VERSION 5.8 ;
BUSBITCHARS "[]" ;
DIVIDERCHAR "/" ;
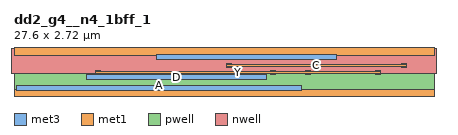
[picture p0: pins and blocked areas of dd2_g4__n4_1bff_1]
MACRO dd2_g4__n4_1bff_1
  CLASS CORE ;
  ORIGIN 0 0 ;
  SIZE 27.600 BY 2.720 ;
  SYMMETRY X Y ;
  SITE unithd ;
  PIN A
    DIRECTION INPUT ;
    USE SIGNAL ;
    ANTENNAGATEAREA 0.426000 ;
    PORT
      LAYER met3 ;
        RECT 0.185 0.175 18.915 0.505 ;
    END
  END A
  PIN B
    DIRECTION INPUT ;
    USE SIGNAL ;
    ANTENNAGATEAREA 0.213000 ;
    PORT
      LAYER met3 ;
        RECT 9.385 2.215 21.215 2.545 ;
    END
  END B
  PIN C
    DIRECTION INPUT ;
    USE SIGNAL ;
    ANTENNAGATEAREA 0.213000 ;
    PORT
      LAYER met1 ;
        RECT 13.990 1.670 14.310 1.730 ;
        RECT 25.490 1.670 25.810 1.730 ;
        RECT 13.985 1.730 25.815 1.870 ;
        RECT 13.990 1.870 14.310 1.930 ;
        RECT 25.490 1.870 25.810 1.930 ;
    END
  END C
  PIN D
    DIRECTION INPUT ;
    USE SIGNAL ;
    ANTENNAGATEAREA 0.213000 ;
    PORT
      LAYER met3 ;
        RECT 4.785 0.855 16.615 1.185 ;
    END
  END D
  PIN VGND
    DIRECTION INOUT ;
    USE GROUND ;
    SHAPE ABUTMENT ;
    PORT
      LAYER met1 ;
        RECT 0.000 -0.240 27.600 0.240 ;
    END
  END VGND
  PIN VNB
    DIRECTION INOUT ;
    USE GROUND ;
    PORT
      LAYER pwell ;
        RECT 0.000 0.000 27.600 1.305 ;
    END
  END VNB
  PIN VPB
    DIRECTION INOUT ;
    USE POWER ;
    PORT
      LAYER nwell ;
        RECT -0.190 1.305 27.790 2.910 ;
    END
  END VPB
  PIN VPWR
    DIRECTION INOUT ;
    USE POWER ;
    SHAPE ABUTMENT ;
    PORT
      LAYER met1 ;
        RECT 0.000 2.480 27.600 2.960 ;
    END
  END VPWR
  PIN Y
    DIRECTION OUTPUT ;
    USE SIGNAL ;
    ANTENNADIFFAREA 1.162800 ;
    PORT
      LAYER met1 ;
        RECT 5.365 1.230 5.685 1.290 ;
        RECT 16.865 1.230 17.185 1.290 ;
        RECT 19.165 1.230 19.485 1.290 ;
        RECT 23.765 1.230 24.085 1.290 ;
        RECT 5.360 1.290 24.090 1.430 ;
        RECT 5.365 1.430 5.685 1.490 ;
        RECT 16.865 1.430 17.185 1.490 ;
        RECT 19.165 1.430 19.485 1.490 ;
        RECT 23.765 1.430 24.085 1.490 ;
    END
  END Y
  OBS
    LAYER li1 ;
      RECT 0.000 -0.085 27.600 0.085 ;
      RECT 1.490 0.085 1.660 0.255 ;
      RECT 12.990 0.085 13.160 0.255 ;
      RECT 15.290 0.085 15.460 0.255 ;
      RECT 1.410 0.255 1.740 0.635 ;
      RECT 12.910 0.255 13.240 0.635 ;
      RECT 15.210 0.255 15.540 0.635 ;
      RECT 0.910 0.255 1.240 0.380 ;
      RECT 0.760 0.380 1.240 0.710 ;
      RECT 5.510 0.255 5.840 0.380 ;
      RECT 5.360 0.380 5.840 0.710 ;
      RECT 6.010 0.255 6.340 0.380 ;
      RECT 6.010 0.380 6.380 0.710 ;
      RECT 7.810 0.255 8.140 0.380 ;
      RECT 7.660 0.380 8.140 0.710 ;
      RECT 8.310 0.255 8.640 0.380 ;
      RECT 8.310 0.380 8.680 0.710 ;
      RECT 10.110 0.255 10.440 0.380 ;
      RECT 9.960 0.380 10.440 0.710 ;
      RECT 10.610 0.255 10.940 0.380 ;
      RECT 10.610 0.380 10.980 0.710 ;
      RECT 12.410 0.255 12.740 0.380 ;
      RECT 12.260 0.380 12.740 0.710 ;
      RECT 14.710 0.255 15.040 0.380 ;
      RECT 14.560 0.380 15.040 0.710 ;
      RECT 0.165 0.380 0.515 0.710 ;
      RECT 0.165 0.710 0.335 1.075 ;
      RECT 0.165 1.075 1.340 1.315 ;
      RECT 2.465 0.380 2.815 0.710 ;
      RECT 2.465 0.710 2.635 1.075 ;
      RECT 2.465 1.075 3.640 1.315 ;
      RECT 4.765 0.380 5.115 0.710 ;
      RECT 4.765 0.710 4.935 1.075 ;
      RECT 4.765 1.075 5.940 1.315 ;
      RECT 7.065 0.380 7.415 0.710 ;
      RECT 7.065 0.710 7.235 1.075 ;
      RECT 7.065 1.075 8.240 1.315 ;
      RECT 9.365 0.380 9.715 0.710 ;
      RECT 9.365 0.710 9.535 1.075 ;
      RECT 9.365 1.075 10.540 1.315 ;
      RECT 11.665 0.380 12.015 0.710 ;
      RECT 11.665 0.710 11.835 1.075 ;
      RECT 11.665 1.075 12.840 1.315 ;
      RECT 13.965 0.380 14.315 0.710 ;
      RECT 13.965 0.710 14.135 1.075 ;
      RECT 13.965 1.075 15.140 1.315 ;
      RECT 16.265 0.380 16.615 0.710 ;
      RECT 16.265 0.710 16.435 1.075 ;
      RECT 16.265 1.075 17.440 1.315 ;
      RECT 18.565 0.380 18.915 0.710 ;
      RECT 18.565 0.710 18.735 1.075 ;
      RECT 18.565 1.075 19.740 1.315 ;
      RECT 20.865 0.380 21.215 0.710 ;
      RECT 20.865 0.710 21.035 1.075 ;
      RECT 20.865 1.075 22.040 1.315 ;
      RECT 23.165 0.380 23.515 0.710 ;
      RECT 23.165 0.710 23.335 1.075 ;
      RECT 23.165 1.075 24.340 1.315 ;
      RECT 25.465 0.380 25.815 0.710 ;
      RECT 25.465 0.710 25.635 1.075 ;
      RECT 25.465 1.075 26.640 1.315 ;
      RECT 3.210 1.505 3.540 2.010 ;
      RECT 3.060 2.010 3.540 2.340 ;
      RECT 3.210 2.340 3.540 2.465 ;
      RECT 17.010 1.505 17.340 2.010 ;
      RECT 16.860 2.010 17.340 2.340 ;
      RECT 17.010 2.340 17.340 2.465 ;
      RECT 19.310 1.505 19.640 2.010 ;
      RECT 19.160 2.010 19.640 2.340 ;
      RECT 19.310 2.340 19.640 2.465 ;
      RECT 19.810 1.505 20.140 2.010 ;
      RECT 19.810 2.010 20.180 2.340 ;
      RECT 19.810 2.340 20.140 2.465 ;
      RECT 21.610 1.505 21.940 2.010 ;
      RECT 21.460 2.010 21.940 2.340 ;
      RECT 21.610 2.340 21.940 2.465 ;
      RECT 23.910 1.505 24.240 2.010 ;
      RECT 23.760 2.010 24.240 2.340 ;
      RECT 23.910 2.340 24.240 2.465 ;
      RECT 24.410 1.505 24.740 2.010 ;
      RECT 24.410 2.010 24.780 2.340 ;
      RECT 24.410 2.340 24.740 2.465 ;
      RECT 26.210 1.505 26.540 2.010 ;
      RECT 26.060 2.010 26.540 2.340 ;
      RECT 26.210 2.340 26.540 2.465 ;
      RECT 3.710 1.505 4.040 2.465 ;
      RECT 17.510 1.505 17.840 2.465 ;
      RECT 22.110 1.505 22.440 2.465 ;
      RECT 26.710 1.505 27.040 2.465 ;
      RECT 3.790 2.465 3.960 2.635 ;
      RECT 17.590 2.465 17.760 2.635 ;
      RECT 22.190 2.465 22.360 2.635 ;
      RECT 26.790 2.465 26.960 2.635 ;
      RECT 0.000 2.635 27.600 2.805 ;
    LAYER met1 ;
      RECT 0.185 0.380 0.515 0.710 ;
      RECT 2.485 0.380 2.815 0.710 ;
      RECT 4.785 0.380 5.115 0.710 ;
      RECT 5.360 0.380 5.690 0.710 ;
      RECT 6.050 0.380 6.380 0.710 ;
      RECT 7.085 0.380 7.415 0.710 ;
      RECT 7.660 0.380 7.990 0.710 ;
      RECT 8.350 0.380 8.680 0.710 ;
      RECT 9.385 0.380 9.715 0.710 ;
      RECT 9.960 0.380 10.290 0.710 ;
      RECT 10.650 0.380 10.980 0.710 ;
      RECT 12.260 0.380 12.590 0.710 ;
      RECT 13.985 0.380 14.315 0.710 ;
      RECT 14.560 0.380 14.890 0.710 ;
      RECT 16.285 0.380 16.615 0.710 ;
      RECT 18.585 0.380 18.915 0.710 ;
      RECT 20.885 0.380 21.215 0.710 ;
      RECT 25.485 0.380 25.815 0.710 ;
      RECT 0.760 0.380 1.090 0.710 ;
      RECT 11.685 0.380 12.015 0.710 ;
      RECT 23.185 0.380 23.515 0.710 ;
      RECT 0.765 0.710 1.085 0.850 ;
      RECT 3.065 0.790 3.385 0.850 ;
      RECT 11.690 0.710 12.010 0.850 ;
      RECT 23.190 0.710 23.510 0.850 ;
      RECT 0.760 0.850 23.515 0.990 ;
      RECT 0.765 0.990 1.085 1.050 ;
      RECT 3.065 0.990 3.385 1.050 ;
      RECT 11.690 0.990 12.010 1.050 ;
      RECT 23.190 0.990 23.510 1.050 ;
      RECT 24.455 0.790 24.775 0.850 ;
      RECT 26.065 0.790 26.385 0.850 ;
      RECT 24.450 0.850 26.390 0.990 ;
      RECT 24.455 0.990 24.775 1.050 ;
      RECT 26.065 0.990 26.385 1.050 ;
      RECT 6.055 1.670 6.375 1.730 ;
      RECT 7.665 1.670 7.985 1.730 ;
      RECT 9.965 1.670 10.285 1.730 ;
      RECT 6.050 1.730 10.290 1.870 ;
      RECT 6.055 1.870 6.375 1.930 ;
      RECT 7.665 1.870 7.985 1.930 ;
      RECT 9.965 1.870 10.285 1.930 ;
      RECT 3.060 2.010 3.390 2.340 ;
      RECT 16.860 2.010 17.190 2.340 ;
      RECT 19.160 2.010 19.490 2.340 ;
      RECT 19.850 2.010 20.180 2.340 ;
      RECT 21.460 2.010 21.790 2.340 ;
      RECT 23.760 2.010 24.090 2.340 ;
      RECT 24.450 2.010 24.780 2.340 ;
      RECT 26.060 2.010 26.390 2.340 ;
    LAYER met2 ;
      RECT 0.210 0.155 0.490 0.210 ;
      RECT 0.190 0.210 0.510 0.675 ;
      RECT 2.510 0.155 2.790 0.210 ;
      RECT 2.490 0.210 2.810 0.675 ;
      RECT 7.110 0.155 7.390 0.210 ;
      RECT 7.090 0.210 7.410 0.675 ;
      RECT 18.610 0.155 18.890 0.210 ;
      RECT 18.590 0.210 18.910 0.675 ;
      RECT 0.765 0.415 1.085 1.050 ;
      RECT 11.690 0.415 12.010 1.050 ;
      RECT 23.190 0.415 23.510 1.050 ;
      RECT 4.790 0.415 5.110 1.150 ;
      RECT 4.810 1.150 5.090 1.205 ;
      RECT 16.290 0.415 16.610 1.150 ;
      RECT 16.310 1.150 16.590 1.205 ;
      RECT 5.365 0.415 5.685 1.490 ;
      RECT 8.355 0.415 8.675 1.830 ;
      RECT 8.375 1.830 8.655 1.885 ;
      RECT 10.655 0.415 10.975 1.830 ;
      RECT 10.675 1.830 10.955 1.885 ;
      RECT 12.265 0.415 12.585 1.830 ;
      RECT 12.285 1.830 12.565 1.885 ;
      RECT 14.565 0.415 14.885 1.830 ;
      RECT 14.585 1.830 14.865 1.885 ;
      RECT 6.055 0.415 6.375 1.930 ;
      RECT 7.665 0.415 7.985 1.930 ;
      RECT 9.965 0.415 10.285 1.930 ;
      RECT 13.990 0.415 14.310 1.930 ;
      RECT 25.490 0.415 25.810 1.930 ;
      RECT 3.065 0.790 3.385 2.305 ;
      RECT 16.865 1.230 17.185 2.305 ;
      RECT 19.165 1.230 19.485 2.305 ;
      RECT 19.875 0.155 20.155 0.210 ;
      RECT 19.855 0.210 20.175 2.305 ;
      RECT 21.485 0.155 21.765 0.210 ;
      RECT 21.465 0.210 21.785 2.305 ;
      RECT 23.765 1.230 24.085 2.305 ;
      RECT 24.455 0.790 24.775 2.305 ;
      RECT 26.065 0.790 26.385 2.305 ;
      RECT 9.390 0.415 9.710 2.510 ;
      RECT 9.410 2.510 9.690 2.565 ;
      RECT 20.890 0.415 21.210 2.510 ;
      RECT 20.910 2.510 21.190 2.565 ;
    LAYER met3 ;
      RECT 19.850 0.175 21.790 0.505 ;
      RECT 8.350 1.535 14.890 1.865 ;
  END
END dd2_g4__n4_1bff_1
END LIBRARY
